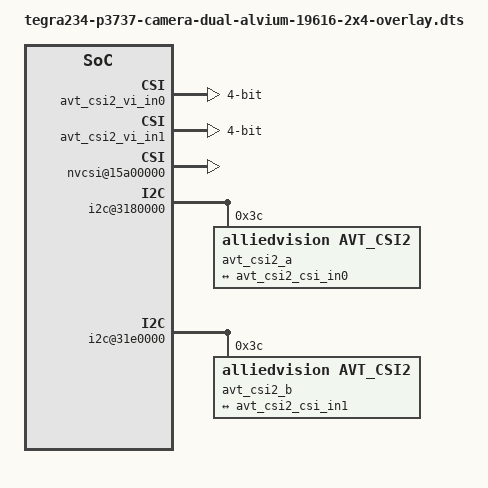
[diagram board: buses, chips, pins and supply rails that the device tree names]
// SPDX-License-Identifier: GPL-2.0-only
/* Allied Vision Alvium CSI2 Driver
 *
 * Copyright (C) 2024 Allied Vision Technologies Gmbh
 * 
 */

/dts-v1/;
/plugin/;

#include <dt-bindings/clock/tegra234-clock.h>
#include <dt-bindings/gpio/tegra234-gpio.h>

#include "alvium-default-mode.h"

/ {
	overlay-name = "DevKit Alvium C Dual 19616 (2x4)";
	jetson-header-name = "Jetson AGX CSI Connector";
	compatible = "nvidia,p3737-0000+p3701-0000", "nvidia,p3737-0000+p3701-0004", "nvidia,p3737-0000+p3701-0005", "nvidia,p3737-0000+p3701-0008";

	fragment@0 {
		target-path = "/";
		__overlay__ {
			tegra-capture-vi {
				status = "okay";
				num-channels = <2>;
				ports {
					#address-cells = <1>;
					#size-cells = <0>;
					status = "okay";
					port@0 {
						status ="okay";
						reg = <0>;
						avt_csi2_vi_in0: endpoint {
							status = "okay";
							port-index = <0>;
							bus-width = <4>;
							remote-endpoint = <&avt_csi2_csi_out0>;
						};
					};

					port@1 {
						status ="okay";
						reg = <1>;
						avt_csi2_vi_in1: endpoint {
							status = "okay";
							port-index = <2>;
							bus-width = <4>;
							remote-endpoint = <&avt_csi2_csi_out1>;
						};
					};
				};
			};

		};
	};

	fragment@1 {
		target-path="/bus@0";
		__overlay__ {
			host1x@13e00000 {
				nvcsi@15a00000 {
					status = "okay";
					num-channels = <2>;
					#address-cells = <1>;
					#size-cells = <0>;

					channel@0 {
						status = "okay";
						reg = <0>;

						ports {
							#address-cells = <1>;
							#size-cells = <0>;
							status = "okay";

							port@0 {
								status = "okay";
								reg = <0>;

								avt_csi2_csi_in0: endpoint@0 {
									status = "okay";
									port-index = <0>;
									bus-width = <4>;
									remote-endpoint = <&avt_csi2_out0>;
								};
							};

							port@1 {
								status = "okay";
								reg = <1>;

								avt_csi2_csi_out0: endpoint@1 {
									status = "okay";
									remote-endpoint = <&avt_csi2_vi_in0>;
								};
							};
						};
					};

					channel@1 {
						status = "okay";
						reg = <1>;
						ports {
							#address-cells = <1>;
							#size-cells = <0>;
							port@0 {
								status = "okay";
								reg = <0>;
								avt_csi2_csi_in1: endpoint@2 {
									status = "okay";
									port-index = <2>;
									bus-width = <4>;
									remote-endpoint = <&avt_csi2_out1>;
								};
							};
							port@1 {
								status = "okay";
								reg = <1>;
								avt_csi2_csi_out1: endpoint@3 {
									status = "okay";
									remote-endpoint = <&avt_csi2_vi_in1>;
								};
							};
						};
					};
				};
			};
		};
	};

	fragment@2 {
		target-path = "/bus@0/i2c@3180000";
		__overlay__ {
			#address-cells = <1>;
			#size-cells = <0>;
			avt_csi2_a@3c {
				status = "okay";
				compatible = "alliedvision,avt_csi2";
				reg = <0x3c>;

				devnode = "video0";
				avt3,userptr;

				ports {
					#address-cells = <1>;
					#size-cells = <0>;

					port@0 {
						reg = <0>;
						avt_csi2_out0: endpoint {
							port-index = <0>;
							bus-width = <4>;
							data-lanes = <1 2 3 4>;
							clock-lanes = <0>;
							link-frequencies = /bits/ 64 <750000000>;
							remote-endpoint = <&avt_csi2_csi_in0>;
						};
					};
				};

				mode0 {
					num_lanes = "4";
					tegra_sinterface = "serial_a";

                    ALVIUM_DEFAULT_MODE
				};
			};

		};
	};

	fragment@3 {
		target-path = "/bus@0/i2c@31e0000";
		__overlay__ {
			avt_csi2_b@3c {
				status = "okay";
                compatible =  "alliedvision,avt_csi2";  
                reg = <0x3c>;

				devnode = "video1";
				avt3,userptr;
			
				ports {
					#address-cells = <1>;
					#size-cells = <0>;

					port@0 {
						reg = <0>;
						avt_csi2_out1: endpoint {
							port-index = <0>;
							bus-width = <4>;
							data-lanes = <1 2 3 4>;
							clock-lanes = <0>;
							link-frequencies = /bits/ 64 <750000000>;
							remote-endpoint = <&avt_csi2_csi_in1>;
						};
					};
				};

				mode0 {
					num_lanes = "4";
					tegra_sinterface = "serial_c";
					
                    ALVIUM_DEFAULT_MODE
				};
			};
		};
	};

	fragment@4 {
		target-path = "/";
		__overlay__ {
			avt_csitl {
				supported_data_types = [ 31 ];
				min_announced_frames = <1>;

				ipu {
					y_min = <32>;
					y_inc = <1>;
					y_max = <32768>;
					x_min = <256>;
					x_inc = <192>;
					x_max = <32768>;
				};
			};

			tegra-camera-platform {
				status = "okay";

				num_csi_lanes = <8>;
				max_lane_speed = <1500000>;
				min_bits_per_pixel = <8>;
				vi_peak_byte_per_pixel = <2>;
				vi_bw_margin_pct = <25>;
				max_pixel_rate = <7500000>;
				isp_peak_byte_per_pixel = <5>;
				isp_bw_margin_pct = <25>;

				modules {
					status = "okay";

					module0 {
						status = "okay";
						badge = "avt_csi2";
						position = "front";
						orientation = "1";

						drivernode0 {
							status = "okay";
							/* Declare PCL support driver (classically known as guid)  */
							pcl_id = "v4l2_sensor";
							/* Driver v4l2 device name */
							devname = "avt_csi2 2-003c";
							/* Declare the device-tree hierarchy to driver instance */
							proc-device-tree = "/proc/device-tree/bus@0/i2c@3180000/avt_csi2@3c";
						};
					};
				};
			};
		};
	};

	fragment@5 {
		target-path = "/bus@0";
		__overlay__ {
			/* The alvium adapter pcb allows to use the pwdn pins for triggering,
			   so make them available to the user. */
			gpio@2200000 {
				camera-control-output-low {
					gpios = <>;
				};
			};
		};
	};
};
